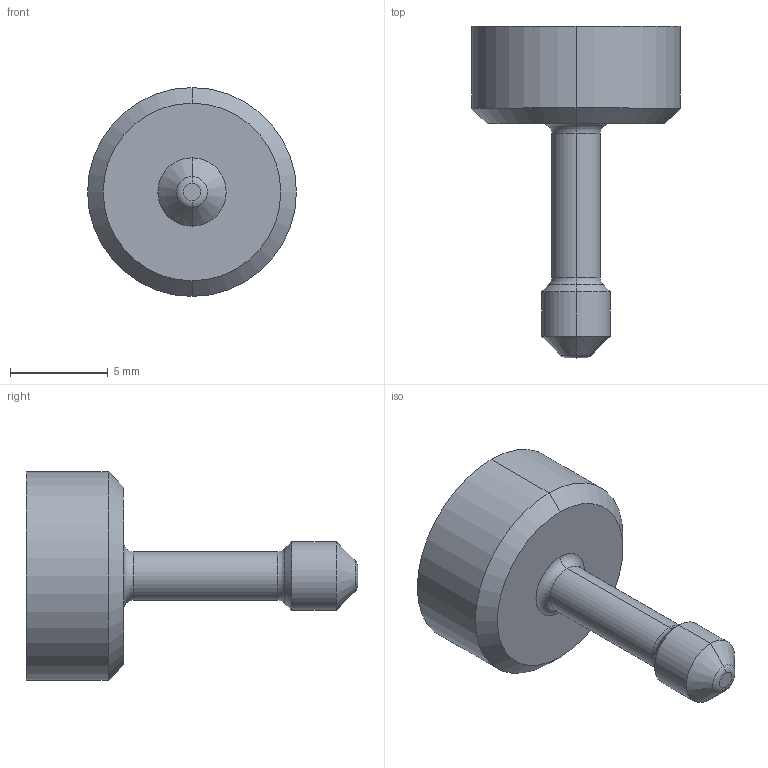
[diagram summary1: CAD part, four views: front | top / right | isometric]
STEP (ISO 10303-21) file: header records copied from the file, then geometry measured from it (millimetres).
FILE_DESCRIPTION (( 'STEP AP214' ), '1' );
FILE_NAME ('IA 100720.STEP', '2013-10-02T07:47:16', ( '' ), ( '' ), 'SwSTEP 2.0', 'SolidWorks 2011', '' );
FILE_SCHEMA (( 'AUTOMOTIVE_DESIGN' ));
Length unit declared in the file: millimetre
Products named in the file (1): IA 100720
Bounding box: 10.7 x 17 x 10.7 mm (x, y, z)
Volume: 504.2 mm3; surface area: 448.9 mm2
Topology: 1 solids, 1 shells, 54 faces, 127 edges, 80 vertices
Faces by surface type: plane 22, cylinder 20, torus 6, cone 6
Entity records: 1611 total; most frequent: DIRECTION 293, CARTESIAN_POINT 262, ORIENTED_EDGE 254, EDGE_CURVE 127, AXIS2_PLACEMENT_3D 111, VERTEX_POINT 80, LINE 71, VECTOR 71
One B-rep face of a CAD part: STEP entity #945.
In plain terms, the planar face has unit normal (0, -1, 0).
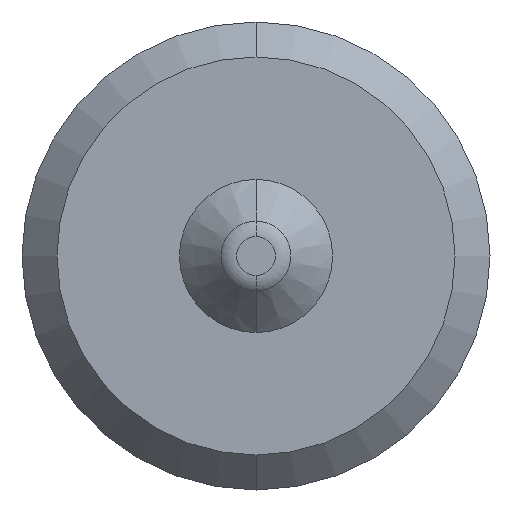
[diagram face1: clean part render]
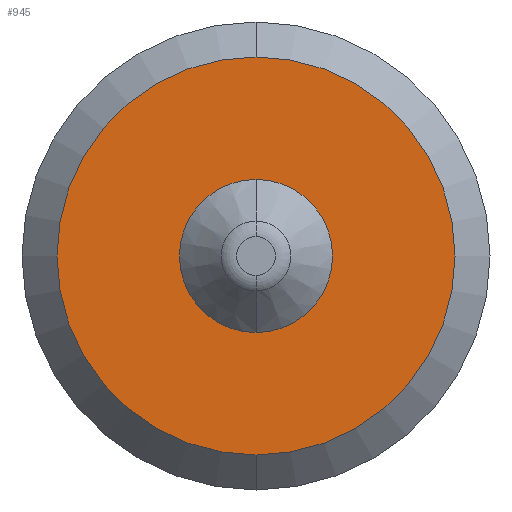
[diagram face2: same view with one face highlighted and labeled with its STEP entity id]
Its self-contained STEP definition (entity closure, numbers rounded to 3 decimals):
#268 = DIRECTION ( 'NONE',  ( 0., 1., 0. ) ) ;
#269 = DIRECTION ( 'NONE',  ( 0., 0., 1. ) ) ;
#294 = CARTESIAN_POINT ( 'NONE',  ( 0., -5., 0. ) ) ;
#301 = DIRECTION ( 'NONE',  ( 0., 1., 0. ) ) ;
#307 = CARTESIAN_POINT ( 'NONE',  ( 0., -5., 0. ) ) ;
#309 = DIRECTION ( 'NONE',  ( 0., 0., 1. ) ) ;
#561 = VERTEX_POINT ( 'NONE', #681 ) ;
#568 = VERTEX_POINT ( 'NONE', #687 ) ;
#614 = VERTEX_POINT ( 'NONE', #745 ) ;
#626 = EDGE_LOOP ( 'NONE', ( #1131, #1113 ) ) ;
#633 = EDGE_LOOP ( 'NONE', ( #1127, #1348 ) ) ;
#645 = VERTEX_POINT ( 'NONE', #733 ) ;
#681 = CARTESIAN_POINT ( 'NONE',  ( 0., -5., -1.75 ) ) ;
#687 = CARTESIAN_POINT ( 'NONE',  ( 0., -5., 1.75 ) ) ;
#733 = CARTESIAN_POINT ( 'NONE',  ( 0., -5., 4.55 ) ) ;
#745 = CARTESIAN_POINT ( 'NONE',  ( 0., -5., -4.55 ) ) ;
#784 = DIRECTION ( 'NONE',  ( 0., 0., 1. ) ) ;
#796 = CARTESIAN_POINT ( 'NONE',  ( 0., -5., 0. ) ) ;
#797 = CARTESIAN_POINT ( 'NONE',  ( 0., -5., 0. ) ) ;
#800 = DIRECTION ( 'NONE',  ( 0., 0., 1. ) ) ;
#807 = DIRECTION ( 'NONE',  ( 0., 1., 0. ) ) ;
#812 = DIRECTION ( 'NONE',  ( 0., 1., 0. ) ) ;
#858 = PLANE ( 'NONE',  #1388 ) ;
#863 = FACE_OUTER_BOUND ( 'NONE', #626, .T. ) ;
#879 = DIRECTION ( 'NONE',  ( 0., 0., -1. ) ) ;
#881 = CARTESIAN_POINT ( 'NONE',  ( -4.55, -5., 0. ) ) ;
#892 = DIRECTION ( 'NONE',  ( 0., -1., 0. ) ) ;
#896 = FACE_BOUND ( 'NONE', #633, .T. ) ;
#922 = EDGE_CURVE ( 'NONE', #561, #568, #1366, .T. ) ;
#923 = EDGE_CURVE ( 'NONE', #645, #614, #1369, .T. ) ;
#945 = ADVANCED_FACE ( 'NONE', ( #896, #863 ), #858, .T. ) ;
#1038 = EDGE_CURVE ( 'NONE', #568, #561, #1529, .T. ) ;
#1042 = EDGE_CURVE ( 'NONE', #614, #645, #1552, .T. ) ;
#1113 = ORIENTED_EDGE ( 'NONE', *, *, #1042, .F. ) ;
#1127 = ORIENTED_EDGE ( 'NONE', *, *, #1038, .T. ) ;
#1131 = ORIENTED_EDGE ( 'NONE', *, *, #923, .F. ) ;
#1348 = ORIENTED_EDGE ( 'NONE', *, *, #922, .T. ) ;
#1366 = CIRCLE ( 'NONE', #1368, 1.75 ) ;
#1368 = AXIS2_PLACEMENT_3D ( 'NONE', #797, #812, #784 ) ;
#1369 = CIRCLE ( 'NONE', #1371, 4.55 ) ;
#1371 = AXIS2_PLACEMENT_3D ( 'NONE', #796, #807, #800 ) ;
#1388 = AXIS2_PLACEMENT_3D ( 'NONE', #881, #892, #879 ) ;
#1484 = AXIS2_PLACEMENT_3D ( 'NONE', #294, #301, #309 ) ;
#1529 = CIRCLE ( 'NONE', #1484, 1.75 ) ;
#1552 = CIRCLE ( 'NONE', #1593, 4.55 ) ;
#1593 = AXIS2_PLACEMENT_3D ( 'NONE', #307, #268, #269 ) ;
